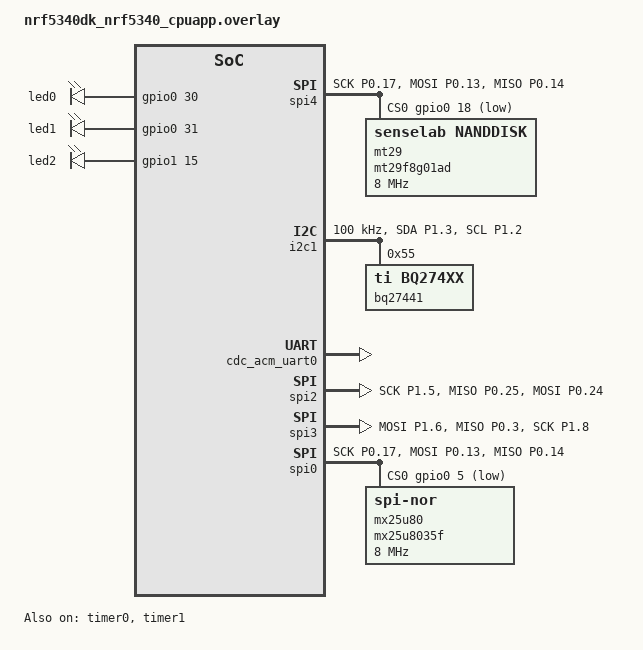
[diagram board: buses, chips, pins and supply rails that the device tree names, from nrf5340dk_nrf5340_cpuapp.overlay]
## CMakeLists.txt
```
# SPDX-License-Identifier: Apache-2.0

# This is a general purpose project created from MotionSenseHRV to be used for data collection.

# Ohio State SENSE LAB
cmake_minimum_required(VERSION 3.20.0)

list(APPEND ZEPHYR_EXTRA_MODULES ${CMAKE_CURRENT_SOURCE_DIR}/src/drivers)

find_package(Zephyr REQUIRED HINTS $ENV{ZEPHYR_BASE})
project(MotionSenseHrv)

set(CMAKE_OBJECT_PATH_MAX 380)
if((NOT CONFIG_DISK_DRIVER_FLASH) AND
   (NOT CONFIG_DISK_DRIVER_RAM) AND
   (NOT CONFIG_DISK_DRIVER_SDMMC))
	message(WARNING "No disk access settings detected." )
endif()
#
#we previously used GLOB_RECURSE, but that was deprecated since we want to have control over what code is included.
FILE(GLOB_RECURSE app_sources src/*.cc)
FILE(GLOB c_app_sources src/*.c)

target_compile_options(app PRIVATE -Wno-unused-function)
#eventually, remove the induvidual file in target_sources, and just refactor to move zephyr filesystem out.
#OR Keep Global Recuse on.
# also move the drivers over to a seperate folder.
target_sources(app PRIVATE ${app_sources} 
${c_app_sources} )

#if(CONFIG_BUILD_WITH_TFM)
#  target_include_directories(app PRIVATE
#    $<TARGET_PROPERTY:tfm,TFM_BINARY_DIR>/install/interface/include
#  )
#endif()
```

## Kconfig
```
# Copyright (c) 2019-2020 Nordic Semiconductor ASA
# SPDX-License-Identifier: Apache-2.0

config APP_WIPE_STORAGE
	bool "Option to clear the flash area before mounting"
	help
	  Use this to force an existing file system to be created.

choice
	prompt "Storage and file system type used by the application"
	default APP_MSC_STORAGE_NONE
	help
	  Specify the type of storage and file system.

config APP_MSC_STORAGE_NONE
	bool "Use RAM disk as block device"
	imply DISK_DRIVER_RAM

config APP_MSC_STORAGE_RAM
	bool "Use RAM disk and FAT file system"
	imply DISK_DRIVER_RAM
	imply FILE_SYSTEM
	imply FAT_FILESYSTEM_ELM

config APP_MSC_STORAGE_FLASH_FATFS
	bool "Use FLASH disk and FAT file system"
	imply DISK_DRIVER_FLASH
	imply FILE_SYSTEM
	imply FAT_FILESYSTEM_ELM

config APP_MSC_STORAGE_FLASH_LITTLEFS
	bool "Use FLASH disk and LittleFS"
	imply DISK_DRIVER_FLASH
	imply FILE_SYSTEM
	imply FILE_SYSTEM_LITTLEFS

config APP_MSC_STORAGE_SDCARD
	bool "Use SDHC and FAT file system"
	imply DISK_DRIVER_SDMMC
	imply FILE_SYSTEM
	imply FAT_FILESYSTEM_ELM

endchoice

config MASS_STORAGE_DISK_NAME
	default "MX25R64" if DISK_DRIVER_FLASH
	default "RAM" if DISK_DRIVER_RAM
	default "SD" if DISK_DRIVER_SDMMC

if DISK_DRIVER_FLASH

config FLASH_MAP
	default y

config FLASH_PAGE_LAYOUT
	default y

config FLASH_LOG_LEVEL
	default 3

if NORDIC_QSPI_NOR

config NORDIC_QSPI_NOR_FLASH_LAYOUT_PAGE_SIZE
	default 4096

endif # NORDIC_QSPI_NOR

endif # DISK_DRIVER_FLASH

config MSENSE3_BLUETOOTH_DATA_UPDATES
	bool "Use MotionSenseHRV3Updates"
	default n
	help 
		Enables the Previous MSense3 mode of data collection, which starts collection as soon as the device connects to usb
		and sends data all through bluetooth
		

menuconfig COLLECTION_REQUIRES_DATE_ID
	bool "Allows sensor collection only if the date time and id characteristics have been filled out by the central."
	default n

config USB_ALWAYS_ON
	bool "whether the usb mass storage driver is on during bluetooth collection"
	default n
	help
		Normally, when data collection starts the USB module turns off, preventing the user from being able to read the drive 
		while data collection is taking place. This KConfig disables this, allowing users to always see logs

config USB_WRITABLE
	bool "whether one can write or modify files via USB"
	default n
	help 
		If the device is plugged in via USB and this KConfig is not set, Users will not be able to create or write new files
		(they can still read them).
		for this to truly work, we must be using a file system driver that supports reading and writing, 
		like flash area (NOR) or dhara (NAND)

config MSENSE_USB_SECURITY
	bool "Configures USB security mode, which requires a password in order to enable to usb behavior. Not Currently Implemented."
	default n

config LOG_BACKEND_FS_BUFFER
    bool "file buffered log backend"
    depends on LOG
    select LOG_OUTPUT
    help
      When enabled, the double buffered filesystem backend (normally for ppg and accel) will be used for logging.

config LOG_LEVEL_IMU_COLLECTION
	int "level at which data from imu is printed in logs"
	default 3

config LOG_LEVEL_PPG_COLLECTION
	int "level at which data from ppg is printed in logs"
	default 3

config LOG_LEVEL_MAX30001
	int "level at which data from MAX30001 is printed in logs"
	default 3

source "Kconfig.zephyr"
```

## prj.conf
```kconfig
#CONFIG_NCS_SAMPLES_DEFAULTS=y

CONFIG_STDOUT_CONSOLE=y

# deprecated:
#CONFIG_CPLUSPLUS=y
#CONFIG_STD_CPP11=y
#CONFIG_NEWLIB_LIBC=y
#CONFIG_LIB_CPLUSPLUS=y

#CONFIG_DEBUG=n
CONFIG_DEBUG_OPTIMIZATIONS=n
#CONFIG_SIZE_OPTIMIZATIONS=y
#CONFIG_SPEED_OPTIMIZATIONS=y

# These KConfigs will dump the entire core into the logs. Useful for debugging a crash.
#CONFIG_DEBUG_COREDUMP=y
#CONFIG_DEBUG_COREDUMP_BACKEND_LOGGING=y
CONFIG_DEBUG_INFO=y
CONFIG_EXCEPTION_STACK_TRACE=y
CONFIG_RESET_ON_FATAL_ERROR=y

#Log config
CONFIG_LOG=y
CONFIG_LOG_DEFAULT_LEVEL=2
# LOG_MODE_MIMIMAL Processes logs in the thread that they are in.
CONFIG_LOG_MODE_MINIMAL=n
#CONFIG_LOG_MODE_DEFERRED=n
#CONFIG_LOG_MODE_IMMEDIATE=n
# this makes prink messages go through the LOG system.
CONFIG_LOG_PRINTK=y
# typically logging is seperate from printk, so this just let's printk output go to console.
CONFIG_PRINTK=y
CONFIG_LOG_MAX_LEVEL=4
# Additional Logging Settings
# this makes the logs have color according to their condition in the serial monitor or terminal.
# so, errors are red, and warnings are yellow.
# in the filesystem, you will need to have an ascii color text processor, otherwise you will see unknown characters and no colors.
CONFIG_LOG_BACKEND_SHOW_COLOR=y
# if we using the deffered log proessing, we have these options avalible:
# LOG_MODE_DEFFERED auto turns this on. deffered mode makes the logs go to a seperate thread instead, which we currently use.
CONFIG_LOG_PROCESS_THREAD=y
#CONFIG_LOG_PROCESS_THREAD_CUSTOM_PRIORITY=
# we need this since our usb takes a few seconds to initialize, and so we miss messages if we don't do a late log startup.
CONFIG_LOG_PROCESS_THREAD_STARTUP_DELAY_MS=8000
#CONFIG_LOG_PROCESS_TRIGGER_THRESHOLD=0
# THREAD_SLEEP_MS is how long the logging thread will periodically sleep after processing messages. 
CONFIG_LOG_PROCESS_THREAD_SLEEP_MS=4000
CONFIG_LOG_PROCESS_THREAD_STACK_SIZE=4096
CONFIG_LOG_BUFFER_SIZE=20000

# Custom Config we created to allow the usb to remain on even when data is collecting, so that we can see the logs. Without this we can't 
#see logs through USB.
CONFIG_USB_ALWAYS_ON=y

CONFIG_NRFX_RTC0=y

# The thread analyser is a cool logging tool that shows how full stacks are for running threads. It can be used to detect stack overflow errors.
CONFIG_THREAD_ANALYZER=y
CONFIG_THREAD_ANALYZER_USE_LOG=y
CONFIG_THREAD_ANALYZER_AUTO=y
CONFIG_THREAD_ANALYZER_AUTO_INTERVAL=10
CONFIG_THREAD_NAME=y
CONFIG_THREAD_MONITOR=y

# when working with the MSense Devices, the only debugging tool we have is the SEGGER_RTT and USB debug output. 
# We have a USB, but we have to set it up via CDC UART (CDC is a usb communication protocol) on device tree
# at the moment, it appears Segger RTT is required even for UART Console output.
CONFIG_USE_SEGGER_RTT=y
# LOG_BACKEND makes the logging avalible, while the CONSOLE option makes command output
CONFIG_LOG_BACKEND_RTT=y
CONFIG_RTT_CONSOLE=n
# Shell also allows commands to be sent
CONFIG_SHELL=n

#Outputs log through usb
CONFIG_LOG_BACKEND_UART=y
# same here, UART_CONSOLE allows commands to be sent while LOG_BACKEND_UART allows log messages to go out.
CONFIG_UART_CONSOLE=y

#CONFIG_RAM_CONSOLE=n

#CONFIG_LOG_BACKEND_FS=n
#CONFIG_LOG_BACKEND_FS_OUTPUT_CUSTOM=y

# Outputs log through USB
CONFIG_LOG_BACKEND_BLE=y
# Custom MSense File Uploading that uses the double buffer system (zephyrfilesystem.c) to output
CONFIG_LOG_BACKEND_FS_BUFFER=y

# Our MSense boards don't have a DCDC on them. This is necessary for the boards to function, or else they will brick!
#CONFIG_BOARD_ENABLE_DCDC_APP=n
#CONFIG_BOARD_ENABLE_DCDC_NET=n

# Clock Control. This KConfig Controls whether we use a Crystal (XTAL) or RC Oscilator.
CONFIG_CLOCK_CONTROL_NRF_K32SRC_RC=n
CONFIG_CLOCK_CONTROL_NRF_K32SRC_RC_CALIBRATION=n

CONFIG_CLOCK_CONTROL_NRF_K32SRC_XTAL=y

# LFXO bypass is for a rail-to-rail external clock source. This board uses
# the standard LFXO pin routing, so leave bypass disabled.
CONFIG_SOC_LFXO_BYPASS=n
CONFIG_SOC_LFXO_CAP_INT_9PF=y
CONFIG_SOC_HFXO_CAP_INTERNAL=y
CONFIG_SOC_HFXO_CAP_INT_VALUE_X2=25

#Gpio Config
CONFIG_GPIO=y

# On the 5340 dev kit, pins 0.02 and 0.03 are configured as pins for an NFC antenna. Since we are using those pins for ppg,
# we need to use this KConfig to make them behave like normal. Apparently setting it in device tree is not enough, we have to use this KConfig
CONFIG_NFCT_PINS_AS_GPIOS=y

# SPI Config
CONFIG_SPI=y
# we don't have any qspi periperals at the moment, everything is spi.
#CONFIG_NRFX_QSPI=y

#I2C config
CONFIG_I2C=y

# Generic Sensor Drivers that includes the battery monitor sensor.
CONFIG_SENSOR=y

# CMSIS config, which is a DSP and Math library
CONFIG_CMSIS_DSP=y
CONFIG_CMSIS_DSP_BASICMATH=y
CONFIG_CMSIS_DSP_COMPLEXMATH=n
CONFIG_CMSIS_DSP_CONTROLLER=n
CONFIG_CMSIS_DSP_DISTANCE=n
CONFIG_CMSIS_DSP_FASTMATH=y
CONFIG_CMSIS_DSP_FILTERING=y
CONFIG_CMSIS_DSP_MATRIX=y
CONFIG_CMSIS_DSP_STATISTICS=y
CONFIG_CMSIS_DSP_TRANSFORM=n
CONFIG_CMSIS_DSP_SUPPORT=y

# timer config
CONFIG_NRFX_TIMER0=y
CONFIG_NRFX_TIMER1=y

#FPU config
CONFIG_FPU=y
CONFIG_FP_HARDABI=y

# Library for buttons and LEDs
CONFIG_DK_LIBRARY=y

# Enable bluetooth and bonding
CONFIG_BT=y

#CONFIG_BT_BONDABLE=y
#CONFIG_BT_BONDING_REQUIRED=y

CONFIG_BT_DEVICE_APPEARANCE=833

CONFIG_BT_MAX_CONN=1

CONFIG_BT_PERIPHERAL=y
#CONFIG_BT_GAP_PERIPHERAL_PREF_PARAMS=y
# in BLE the host typically sets the minimum and maximum connection interval with which packets must be sent. 
# however, the client can still request preferred parameters and the host can decide if it wants to accept them.
CONFIG_BT_PERIPHERAL_PREF_MAX_INT=48
CONFIG_BT_PERIPHERAL_PREF_MIN_INT=24
CONFIG_BT_PERIPHERAL_PREF_LATENCY=3
# Units are 10 ms: 800 = 8 s, compliant with current Apple 6-18 s guidance (ADG section 55.6).
CONFIG_BT_PERIPHERAL_PREF_TIMEOUT=800
CONFIG_BT_DEVICE_NAME="MSense4PPG-"
CONFIG_BT_DEVICE_NAME_DYNAMIC=y
CONFIG_BT_DEVICE_NAME_MAX=16
CONFIG_BT_DEVICE_NAME_GATT_WRITABLE=n
CONFIG_HWINFO=y
CONFIG_CRC=y

#CONFIG_BT_CTLR=y
#CONFIG_BT_CTLR_TX_PWR_ANTENNA=-8
#CONFIG_BT_CTLR_TX_PWR_MINUS_40=y

# for now, we don't use security, but we can re-enable if we want it.
CONFIG_BT_SMP=n

# Enable device information service for bluetooth
CONFIG_BT_DIS=y
CONFIG_BT_DIS_MANUF="SenseLab"
CONFIG_BT_DIS_PNP=n
CONFIG_BT_DIS_MODEL="5.2.3 Utah Prod"
CONFIG_BT_DIS_SETTINGS=n
CONFIG_BT_MAX_PAIRED=1

# Enable Battery service settings
CONFIG_BT_BAS=y

 

# I belive we do this because the flash reset function has a lot of stack usage.
CONFIG_BT_RX_STACK_SIZE=8192

#DFU/FOTA settings
CONFIG_BOOTLOADER_MCUBOOT=y

CONFIG_NCS_SAMPLE_MCUMGR_BT_OTA_DFU=y
#CONFIG_MCUBOOT_GENERATE_CONFIRMED_IMAGE=y

#CONFIG_MCUMGR_LOG_LEVEL_DBG=n
#CONFIG_MCUMGR_SMP_BT_AUTHEN=n

# Where the bad block table is persisted. The NOR backend keeps it on the external
# NOR next to the file table, which needs no extra partition, so Partition Manager
# produces the same map as devices already in the field and they can still take a
# DFU update. Selecting RAW_NAND_BAD_BLOCK_STORAGE_SETTINGS instead moves it to the
# settings subsystem, which allocates a settings_storage partition and changes the
# map, breaking DFU for those devices.
CONFIG_RAW_NAND_BAD_BLOCK_STORAGE_NOR=y

# Only needed by the settings backend above. Enabling SETTINGS_NVS is what makes
# Partition Manager carve out settings_storage.
CONFIG_SETTINGS=n
#CONFIG_SETTINGS_NVS=y
#CONFIG_NVS=y

#CONFIG_SETTINGS_NVS_SECTOR_COUNT=8
# The default 0x2000 only gives NVS two sectors, one of which is always reserved
# for garbage collection. 0x4000 gives it four and matches FPROTECT_BLOCK_SIZE on
# the nRF5340, which the partition has to start on anyway, so nothing is wasted
# on alignment padding.
#CONFIG_BT_SETTINGS=y
#CONFIG_SETTINGS_RUNTIME=y

#CONFIG_SETTINGS_NONE=y

# not sure what this is
#CONFIG_MPU_ALLOW_FLASH_WRITE=y

CONFIG_TEST_RANDOM_GENERATOR=y
CONFIG_TIMER_RANDOM_GENERATOR=y

# Flash Driver Config
# CRC library, used to sanity check the file table stored on the NOR
CONFIG_CRC=y
CONFIG_SPI_NOR=y
CONFIG_FLASH=y
# QSPI Driver for QSPI Nor Flash. No longer used as we use NAND for storage.
CONFIG_NORDIC_QSPI_NOR=n
CONFIG_FLASH_MAP=y
CONFIG_FLASH_PAGE_LAYOUT=y
CONFIG_FLASH_LOG_LEVEL_INF=y
#CONFIG_SPI_NOR_FLASH_LAYOUT_PAGE_SIZE=4096

# Partition Manager Config

CONFIG_PM_EXTERNAL_FLASH_MCUBOOT_SECONDARY=n

# Disk Driver Config
CONFIG_DISK_DRIVER_FLASH=n
CONFIG_DISK_DRIVER_RAM=n
CONFIG_DISK_DRIVER_RAW_NAND=y
CONFIG_DISK_DRIVER_DHARA=n

CONFIG_RAW_NAND_BAD_BLOCK_SAVING=y
CONFIG_RAW_NAND_BAD_BLOCK_SIMULATION=y
# File System Config
CONFIG_FILE_SYSTEM=y
# needed because of our BT DFU external flash image which forces us to use partition manager.
CONFIG_PM_OVERRIDE_EXTERNAL_DRIVER_CHECK=y
CONFIG_MASS_STORAGE_DISK_NAME="SD"
#CONFIG_FILE_SYSTEM_LITTLEFS=y
# ELM Chan's fat filesystem library
CONFIG_FAT_FILESYSTEM_ELM=y
# we implement this dynamically by remounting the file system as read only.
CONFIG_FS_FATFS_READ_ONLY=n

# below config is necessary because this determines the buffer fatfs internally uses to store reads which we do at a size of 4096
CONFIG_FS_FATFS_MAX_SS=4096
CONFIG_FS_FATFS_EXFAT=n
CONFIG_FS_FATFS_MAX_ROOT_ENTRIES=4096
CONFIG_FS_FATFS_LFN=y

# we no longer use little fs since there is no built in computer file system support on USB mass.
#CONFIG_FS_LITTLEFS_CACHE_SIZE=128
#CONFIG_FS_LITTLEFS_READ_SIZE=16
#CONFIG_FS_LITTLEFS_PROG_SIZE=16

#USB related configs
CONFIG_USB_DEVICE_STACK=y
CONFIG_USB_DEVICE_PRODUCT="MSense4 USB Mass"
CONFIG_USB_DEVICE_PID=0x0008
CONFIG_USB_MASS_STORAGE=y

CONFIG_USB_MAX_POWER=100
CONFIG_USB_DEVICE_LOG_LEVEL_INF=y
# this log handles where the usb mass throws errors.
CONFIG_USB_MASS_STORAGE_LOG_LEVEL_ERR=y

CONFIG_USB_DEVICE_INITIALIZE_AT_BOOT=n
CONFIG_MASS_STORAGE_STACK_SIZE=4096

# Previous method of data gathering, where data from sensors is sent through bluetooth instead of the file system.
CONFIG_MSENSE3_BLUETOOTH_DATA_UPDATES=n

CONFIG_MSENSE_USB_SECURITY=n

# IMU and PPG logs
CONFIG_LOG_LEVEL_IMU_COLLECTION=3
CONFIG_LOG_LEVEL_PPG_COLLECTION=3

# General System Memory and stack Configs
CONFIG_SYSTEM_WORKQUEUE_STACK_SIZE=20192
CONFIG_SYSTEM_WORKQUEUE_PRIORITY=-5
#CONFIG_SYSTEM_WORKQUEUE_NO_YIELD=y

CONFIG_HEAP_MEM_POOL_SIZE=5384
CONFIG_MAIN_STACK_SIZE=20192

# File system encryption (src/fs_crypt.c): AES on the CryptoCell-312 through PSA.
# Bluetooth keeps using TinyCrypt; nothing here changes it.
CONFIG_NRF_SECURITY=y
CONFIG_MBEDTLS_PSA_CRYPTO_C=y
CONFIG_PSA_CRYPTO_DRIVER_CC3XX=y
CONFIG_PSA_CRYPTO_DRIVER_OBERON=n
CONFIG_PSA_WANT_KEY_TYPE_AES=y
CONFIG_PSA_WANT_AES_KEY_SIZE_128=y
CONFIG_PSA_WANT_ALG_ECB_NO_PADDING=y
# psa_crypto_init() also brings up the random number generator
CONFIG_PSA_WANT_GENERATE_RANDOM=y
CONFIG_MBEDTLS_ENABLE_HEAP=y
CONFIG_MBEDTLS_HEAP_SIZE=8192
```

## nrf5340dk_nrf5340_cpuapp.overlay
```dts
// press Ctrl+Space to bring up the completion menu and view the available nodes.

// You can also use the buttons in the sidebar to perform actions on nodes.
// Actions currently available include:

// * Enabling / disabling the node
// * Adding the bus to a bus
// * Removing the node
// * Connecting ADC channels

// For more help, browse the DeviceTree documentation at https://docs.zephyrproject.org/latest/guides/dts/index.html
// You can also visit the nRF DeviceTree extension documentation at https://nrfconnect.github.io/vscode-nrf-connect/devicetree/nrfdevicetree.html

/* Begin dk trim section, that removes all dev kit specific nodes. */

&spi1 {
    status = "disabled";
};

&spi4 {
	status = "disabled";
};

&qspi {
	status = "disabled";
};

&uart0 {
	status = "okay";
};

&i2c1 {
	status = "disabled";
};

&pwm0 {
	status = "disabled";
};

&led0 {
    status = "okay";
	gpios = <&gpio0 30 GPIO_ACTIVE_HIGH>;
};

&led1 {
    status = "okay";
    gpios = <&gpio0 31 GPIO_ACTIVE_HIGH>;
};

&led2 {
    status = "okay";
	gpios = <&gpio1 15 GPIO_ACTIVE_HIGH>;
};

&led3 {
    status = "disabled";
};

&button0 {
    status = "disabled";
};

&button1 {
    status = "disabled";
};

&button2 {
    status = "disabled";
};

&button3 {
    status = "disabled";
};

&gpio_fwd {
	status = "okay";
};

/* End dev kit trim section */

&timer0 {
    status = "okay";
};

&timer1 {
    status = "okay";
};

&arduino_adc {
    io-channel-map = <0 &adc 0>, <1 &adc 1>, <2 &adc 2>, <3 &adc 3>, <4 &adc 4>, <5 &adc 5>;
};

/ {
    aliases {
        customspi = &spi1;
		spi-flash0 = &mt29;
		spi-flash1 = &mx25u80;
    };
};

/ {
	chosen {
	
		//nordic,pm-ext-flash = &mt29;
		zephyr,console = &cdc_acm_uart0;
        zephyr,shell-uart = &cdc_acm_uart0;
		
		};
	};
	

///delete-node/ &storage_partition;

//uart cannot also be in operation with spi0, however, this means we have to use segger RTT, because uart is used for console output
&uart0 {
	status = "disabled";
};

 
&zephyr_udc0 {
    cdc_acm_uart0: cdc_acm_uart0 {
        compatible = "zephyr,cdc-acm-uart";
    };
};

&spi2 {
compatible = "nordic,nrf-spim";
	status = "okay";
	cs-gpios = <&gpio0 26 GPIO_ACTIVE_LOW>;
	pinctrl-0 = <&spi1_default>;
	pinctrl-1 = <&spi1_sleep>;
	pinctrl-names = "default", "sleep";

};

// We need to disable i2c1, since we are already using spi1 and it is no longer needed (can't have 2 devices on the same unit).
&i2c1 {
	compatible = "nordic,nrf-twim";
	status = "okay";

	clock-frequency = <I2C_BITRATE_STANDARD>;

	pinctrl-0 = <&battery_default>;
	pinctrl-1 = <&battery_sleep>;
	pinctrl-names = "default", "sleep";
	bq27441@55 {
		compatible = "ti,bq274xx";
        reg = <0x55>;
        design-voltage = <3700>;
        design-capacity = <300>;
        taper-current = <30>;
        terminate-voltage = <3000>;
	};
};

/* 
&i2c0 {
	status = "okay";
	compatible = "nordic,nrf-twim";
	pinctrl-0 = < &i2c1_default>;
	pinctrl-1 = <&i2c1_sleep>;
	pinctrl-names = "default", "sleep";
};
*/

&spi3{
	compatible = "nordic,nrf-spim";
	status = "okay";
	cs-gpios = <&gpio1 9 GPIO_ACTIVE_LOW>;
	pinctrl-0 = <&ppg_default>;
	pinctrl-1 = <&ppg_sleep>;
	pinctrl-names = "default", "sleep";
};

//External Flash, MX25 NOR 

&spi0 {
	status = "okay";
	pinctrl-0 = <&spi_flash_default>;
	pinctrl-1 = <&spi_flash_sleep>;
	pinctrl-names = "default", "sleep";
	cs-gpios = <&gpio0 5 GPIO_ACTIVE_LOW>;
	mx25u80: mx25u8035f@0 {
		compatible = "jedec,spi-nor";
		// size needs to be in bits for nor
		//size = <1073725440>;
		size = <8388608>;
		reg = <0>;
		spi-max-frequency = <8000000>;
		jedec-id = [c2 25 34];
		status = "okay";
	};

};

// External Flash, MT29 NAND

&spi4 {
	status = "okay";
	pinctrl-0 = < &spi_flash_default>;
	pinctrl-1 = <&spi_flash_sleep>;
	pinctrl-names = "default", "sleep";
	cs-gpios = <&gpio0 18 GPIO_ACTIVE_LOW>, <&gpio0 4 GPIO_ACTIVE_LOW>, <&gpio0 21 GPIO_ACTIVE_LOW>, <&gpio0 19 GPIO_ACTIVE_LOW>;
	mt29: mt29f8g01ad@0 {
		compatible = "senselab,nanddisk";
		// size parameter needs to be in bytes
		// 4294901760 bytes is aproximately 4 GB. Updated from 2147450880 bytes (1.99 GB)
		size = <4294901760>;
		reg = <0>;
		spi-max-frequency = <8000000>;
		jedec-id = [ff 2c 47];
		status = "okay";
	};

};

/* 
&qspi {
	status = "okay";
	pinctrl-0 = <&qspi_default>;
	pinctrl-1 = <&qspi_sleep>;
	pinctrl-names = "default", "sleep";
	mx66u: mx66u2g45g@0 {
		compatible = "nordic,qspi-nor";
		//compatible = "vnd,customflash";
		//compatible = "senselab,qspinor";
	reg = <0>;
	//MX25R64 supports only pp and pp4io
	writeoc = "pp4io";
	//MX25R64 supports all readoc options
	readoc = "read4io";
	sck-frequency = <8000000>;
	jedec-id = [c2 25 3c];
	sfdp-bfp = [
		e5 20 f1 ff  ff ff ff 03  44 eb 08 6b  08 3b 04 bb
		ee ff ff ff  ff ff 00 ff  ff ff 00 ff  0c 20 0f 52
		10 d8 00 ff  23 72 f5 00  82 ed 04 cc  44 83 68 44
		30 b0 30 b0  f7 c4 d5 5c  00 be 29 ff  f0 d0 ff ff
	];
	size = <67108864>;
	has-dpd;
	t-enter-dpd = <10000>;
	t-exit-dpd = <35000>;
	};
};
*/

&pinctrl {
	//spi 1, imu sensor
    spi1_default: spi1_default {
		group1 {
			psels = <NRF_PSEL(SPIM_SCK, 1, 5)>,
				<NRF_PSEL(SPIM_MISO, 0, 25)>,
				<NRF_PSEL(SPIM_MOSI, 0, 24)>;
		};
	};

	spi1_sleep: spi1_sleep {
		group1 {
			psels = <NRF_PSEL(SPIM_SCK, 1, 5)>,
				<NRF_PSEL(SPIM_MISO, 0, 25)>,
				<NRF_PSEL(SPIM_MOSI, 0, 24)>;
			low-power-enable;
		};
	};

	
	//spi 4, ppg sensor
	ppg_default: ppg_default {
		group1 {
			psels = <NRF_PSEL(SPIM_MOSI, 1, 6)>, <NRF_PSEL(SPIM_MISO, 0, 3)>, <NRF_PSEL(SPIM_SCK, 1, 8)>;
		};
	};

	ppg_sleep: ppg_sleep {
		group1{
			psels = <NRF_PSEL(SPIM_MOSI, 1, 6)>, <NRF_PSEL(SPIM_MISO, 0, 3)>, <NRF_PSEL(SPIM_SCK, 1, 8)>;
			low-power-enable;
		};
	};
	
	 
	//battery, on i2c0
	battery_default: battery_default {
		group1 {
			psels = <NRF_PSEL(TWIM_SDA, 1, 3)>,
				<NRF_PSEL(TWIM_SCL, 1, 2)>;
		};
	};

	battery_sleep: battery_sleep {
		group1 {
			psels = <NRF_PSEL(TWIM_SDA, 1, 3)>,
				<NRF_PSEL(TWIM_SCL, 1, 2)>;
			low-power-enable;
		};
	};

	
	spi_flash_default: spi_flash_default {
		group1 {
			psels = <NRF_PSEL(SPIM_SCK, 0, 17)>,
				<NRF_PSEL(SPIM_MOSI, 0, 13)>,
				<NRF_PSEL(SPIM_MISO, 0, 14)>;
				
		};
	};
	
	spi_flash_sleep: spi_flash_sleep {
		group1 {
			psels = <NRF_PSEL(SPIM_SCK, 0, 17)>,
			<NRF_PSEL(SPIM_MOSI, 0, 13)>,
			<NRF_PSEL(SPIM_MISO, 0, 14)>;
			low-power-enable;
		};
	};

};
```

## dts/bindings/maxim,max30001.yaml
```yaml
description: MAX30001 ECG analog front-end on SPI

compatible: "maxim,max30001"

include: ["spi-device.yaml"]

properties:
  reg:
    required: true

  intb-gpios:
    type: phandle-array
    description: MAX30001 INTB interrupt GPIO.

  intb2-gpios:
    type: phandle-array
    description: MAX30001 INTB2 interrupt GPIO.
```

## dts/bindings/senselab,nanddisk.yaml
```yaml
description: |
  Zephyr MMC disk node. A binding with this compatible present within an SD
  host controller device node indicates that an SDMMC disk is attached to that
  SD bus. This binding will enable that disk to be used with the disk driver
  API and any subsystems that utilize it.

compatible: "senselab,nanddisk"

include: ["spi-device.yaml", "jedec,spi-nor-common.yaml"]

properties:
  reg:
    required: true

  jedec-id:
    required: true

  size:
    type: int
    description: |
      The size of the flash in bytes.  
```

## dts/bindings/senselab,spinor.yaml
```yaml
description: |
  Zephyr MMC disk node. A binding with this compatible present within an SD
  host controller device node indicates that an SDMMC disk is attached to that
  SD bus. This binding will enable that disk to be used with the disk driver
  API and any subsystems that utilize it.

compatible: "senselab,spinor"

include: ["spi-device.yaml", "jedec,spi-nor-common.yaml"]

properties:
  reg:
    required: true

  jedec-id:
    required: true

  size:
    type: int
    description: |
      The size of the flash in bytes.  
```

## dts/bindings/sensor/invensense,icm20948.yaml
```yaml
# SPDX-License-Identifier: Apache-2.0

description: |
  ICM-20948 accelerometer-only SPI interface used by the MotionSense ECG PCB.

compatible: "invensense,icm20948"

include: spi-device.yaml

properties:
  int-gpios:
    type: phandle-array
    required: true
    description: |
      INT1 data-ready signal. The ICM-20948 is configured as active-high,
      push-pull, and pulse mode.

  fsync-gpios:
    type: phandle-array
    required: true
    description: |
      FSYNC input driven inactive by the host while frame synchronization is
      unused.
```

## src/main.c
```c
/*
 * Copyright (c) 2016 Intel Corporation
 *
 * SPDX-License-Identifier: Apache-2.0
 */

#include <zephyr/kernel.h>
#include <zephyr/devicetree.h>
#include <zephyr/drivers/gpio.h>
#include <zephyr/drivers/spi.h>
#include <zephyr/drivers/i2c.h>
#include <zephyr/drivers/sensor.h>
#include "drivers/nand/nand_disk.h"
#include <nrfx.h>
#include <nrfx_timer.h>
#include <nrfx_uarte.h>
#include <zephyr/logging/log.h>
#include <zephyr/usb/usb_device.h>
#include "batterymonitordt.h"
#include "ppgSensor.h"
#include "imuSensor.h"
#include "common.h"
#include "BLEService.h"
#include "device_identity.h"
#include "fs_crypt_key.h"
#include "zephyrfilesystem.h"
#include <zephyr/shell/shell.h>
#include <zephyr/bluetooth/bluetooth.h>
#include <zephyr/bluetooth/hci.h>
#include <zephyr/bluetooth/uuid.h>
#include <string.h>

LOG_MODULE_REGISTER(main, 3);

/* 1000 msec = 1 sec */
#define SLEEP_TIME_MS 6000

/* The devicetree node identifier for the "led0" alias. */
#define LED_NODE DT_ALIAS(led0)
#define LED1_NODE DT_ALIAS(led1)
#define PPG_POWER_NODE DT_ALIAS(led2) 

// define our red and green leds
#define LED_PIN DT_GPIO_PIN(LED_NODE, gpios)
#define LED1_PIN DT_GPIO_PIN(LED1_NODE, gpios)

#define LED_FLAGS DT_GPIO_FLAGS(LED0_NODE, gpios)

#define PPG_POWER_PIN DT_GPIO_PIN(PPG_POWER_NODE, gpios)
#define PPG_POWER_FLAGS DT_GPIO_FLAGS(PPG_POWER_NODE, gpios)

const struct device* gpio0_device;
const struct device* gpio1_device;

/* SPI Definitions */

/*
------------------------------------------------------------------------------------
SPI Mode    CPOL 	CPHA 	Clock Polarity  Clock Phase Used to
                                in Idle State 	Sample and/or Shift the Data
------------------------------------------------------------------------------------
0               0         0 	Logic low 	Data sampled on rising edge and
                                                shifted out on the falling edge
1               0         1 	Logic low 	Data sampled on the falling edge and
                                                shifted out on the rising edge
2               1         1 	Logic high 	Data sampled on the falling edge and
                                                shifted out on the rising edge
3               1         0 	Logic high 	Data sampled on the rising edge and
                                                shifted out on the falling edge
-------------------------------------------------------------------------------------
*/
// SPI Mode-3 IMU
struct spi_config spi_cfg_imu =
{
    .frequency = 4000000,
    .operation = SPI_WORD_SET(8) | SPI_TRANSFER_MSB |
                 SPI_MODE_CPOL | SPI_MODE_CPHA,
    .slave = 0,
    // this should work, but for some reason it doesn't. However, this might work without
    // the cs field anyway, apparently it is auto managed, so test first
    //.cs = SPI_CS_CONTROL_PTR_DT(DT_NODELABEL(spi2), 0)
    };

// SPI Mode-3 PPG
struct spi_config spi_cfg_ppg = {
    .frequency = 4000000,
    .operation = SPI_WORD_SET(8) | SPI_TRANSFER_MSB |
                 SPI_MODE_CPOL | SPI_MODE_CPHA,
    .slave = 0,
    /* only in version 2.5: .cs= {
  .delay = 0,
  .gpio = {.pin = 15, .dt_flags=GPIO_ACTIVE_LOW, }
  },
  */
};

// Now we define the cs pins

struct spi_cs_control imu_cs = {
    .delay = 0,
    .gpio = {.pin = 26, .dt_flags = GPIO_ACTIVE_LOW}};

struct spi_cs_control ppg_cs = {
    .delay = 0,
    .gpio = {
        .pin = 9,
        .dt_flags = GPIO_ACTIVE_LOW,
    }};

const struct device *spi_dev_ppg, *spi_dev_imu;
const struct device *i2c_dev;

#define DIS_FW_REV_STR CONFIG_BT_DIS_FW_REV_STR
#define DIS_FW_REV_STR_LEN (sizeof(DIS_FW_REV_STR))

#define DIS_HW_REV_STR CONFIG_BT_DIS_HW_REV_STR
#define DIS_HW_REV_STR_LEN (sizeof(DIS_HW_REV_STR))

#define DIS_MANUF CONFIG_BT_DIS_MANUF
#define DIS_MANUF_LEN (sizeof(DIS_MANUF))

#define DIS_MODEL CONFIG_BT_DIS_MODEL
#define DIS_MODEL_LEN (sizeof(DIS_MODEL))

static K_SEM_DEFINE(ble_init_ok, 0, 1);

uint32_t global_counter;

#define AD_FIELD_OVERHEAD 2U
#define AD_FLAGS_ENCODED_LEN (AD_FIELD_OVERHEAD + 1U)
#define AD_SERVICE_DATA_LEN (BT_UUID_SIZE_128 + MSENSE_DEVICE_ID_LEN)
#define AD_SERVICE_DATA_ENCODED_LEN (AD_FIELD_OVERHEAD + AD_SERVICE_DATA_LEN)
#define SCAN_RESPONSE_NAME_ENCODED_LEN (AD_FIELD_OVERHEAD + MSENSE_BLE_NAME_LEN)

static uint8_t advertising_service_data[AD_SERVICE_DATA_LEN] = {
    CONTROL_SERVICE_UUID,
};

static struct bt_data ad[] = {
    BT_DATA_BYTES(BT_DATA_FLAGS, (BT_LE_AD_GENERAL | BT_LE_AD_NO_BREDR)),
    BT_DATA(BT_DATA_SVC_DATA128, advertising_service_data,
            sizeof(advertising_service_data)),
};

static struct bt_data sd[] = {
    {
        .type = BT_DATA_NAME_COMPLETE,
        .data = NULL,
        .data_len = 0U,
    },
};

BUILD_ASSERT(MSENSE_DEVICE_ID_LEN == 8U, "Device ID must be 64 bits");
BUILD_ASSERT(MSENSE_BLE_NAME_LEN == 16U, "BLE name length changed unexpectedly");
BUILD_ASSERT(sizeof(advertising_service_data) == 24U,
             "Service data must contain UUID and device ID");
BUILD_ASSERT(AD_FLAGS_ENCODED_LEN + AD_SERVICE_DATA_ENCODED_LEN <=
             BT_GAP_ADV_MAX_ADV_DATA_LEN,
             "Primary advertising data exceeds the legacy limit");
BUILD_ASSERT(SCAN_RESPONSE_NAME_ENCODED_LEN <= BT_GAP_ADV_MAX_ADV_DATA_LEN,
             "Scan response name exceeds the legacy limit");

// Shell Commands for entering in the terminal, in case a bluetooth command is not avalible.
SHELL_CMD_REGISTER(reset, NULL, "Resets Device", NVIC_SystemReset);
SHELL_CMD_REGISTER(full_reset, NULL, "Resets Storage and Device", reset_device);

// Setting up the device information service
static int settings_runtime_load(void)
{

/*
  settings_runtime_set("bt/dis/model",
                       DIS_MODEL, DIS_MODEL_LEN);
  settings_runtime_set("bt/dis/manuf",
                       DIS_MANUF, DIS_MANUF_LEN);
*/
  return 0;
}

void usb_status_cb(enum usb_dc_status_code status, const uint8_t *param){
    
  LOG_INF("USB Status: %d", status);

  // CONNECTED/DISCONNECTED are raised on VBUS detect/remove, so update the charging bit right away
  // instead of waiting for the next battery_maintenance() pass.
  if (status == USB_DC_CONNECTED || status == USB_DC_DISCONNECTED){
    update_charging_state();
  }

}

static void write_uuid_file(void)
{
  bt_addr_le_t address = {0};
  size_t count = 1;
  char addr_str[BT_ADDR_LE_STR_LEN];
  int result;

  bt_id_get(&address, &count);
  bt_addr_le_to_str(&address, addr_str, sizeof(addr_str));

  result = write_ble_uuid(addr_str, bt_get_name(),
                          msense_device_identity_hex());
  if (result < 0) {
    LOG_ERR("Unable to write uuid.txt: %d", result);
  }
}

static void le_param_updated(struct bt_conn *conn, uint16_t interval, uint16_t latency, uint16_t timeout)
{
  struct bt_conn_info info;
  char addr[BT_ADDR_LE_STR_LEN];

  if (bt_conn_get_info(conn, &info))
    printk("Could not parse connection info\n");
  else
  {
    bt_addr_le_to_str(bt_conn_get_dst(conn), addr, sizeof(addr));
    printk("Connection parameters updated!	\n\
      Connected to: %s						\n\
      New Connection Interval: %u				\n\
      New Slave Latency: %u					\n\
      New Connection Supervisory Timeout: %u	\n",
           addr, info.le.interval, info.le.latency, info.le.timeout);
  }
}

static struct bt_conn_cb conn_callbacks = {
    .connected = connected,
    .disconnected = disconnected,
    //.le_param_req = le_param_req,
    .le_param_updated = le_param_updated};

static void bt_ready(int err)
{
  if (err)
  {
    printk("BLE init failed with error code %d\n", err);
    return;
  }
  else
    printk("BLE init success\n");

  #if CONFIG_BT_SETTINGS
    settings_load();
  #endif

  // Configure connection callbacks
  bt_conn_cb_register(&conn_callbacks);

  err = bt_set_name(msense_device_identity_name());
  if (err) {
    LOG_ERR("Unable to set generated BLE name: %d", err);
    return;
  }

  memcpy(&advertising_service_data[BT_UUID_SIZE_128],
         msense_device_identity_bytes(), MSENSE_DEVICE_ID_LEN);
  sd[0].data = msense_device_identity_name();
  sd[0].data_len = MSENSE_BLE_NAME_LEN;

  // Start advertising
  const struct bt_le_adv_param v = {
      .id = BT_ID_DEFAULT,
      .sid = 0,
      .secondary_max_skip = 0,
      .options = BT_LE_ADV_OPT_CONNECTABLE | BT_LE_ADV_OPT_USE_IDENTITY,
      .interval_min = BT_GAP_ADV_FAST_INT_MIN_2,
      .interval_max = BT_GAP_ADV_FAST_INT_MAX_2,
      .peer = NULL};

  // if this doesn't work we can use
  /* 
  static struct bt_le_adv_param *adv_param = BT_LE_ADV_PARAM((BT_LE_ADV_OPT_CONNECTABLE|BT_LE_ADV_OPT_USE_IDENTITY), 
                800, //Min Advertising Interval 500ms (800*0.625ms) 
                801, //Max Advertising Interval 500.625ms (801*0.625ms)
                NULL); // Set to NULL for undirected advertising
  */
  err = bt_le_adv_start(&v, ad, ARRAY_SIZE(ad), sd, ARRAY_SIZE(sd));
  if (err)
    printk("Advertising failed to start (err %d)\n", err);
  else
  {
    printk("Advertising started\n");
  }

  k_sem_give(&ble_init_ok);

  write_uuid_file();
  #ifndef CONFIG_DEBUG
  
    if (!security_lock){
      usb_enable(usb_status_cb);
    }
    //k_sleep(K_SECONDS(10));
    #if CONFIG_DISK_DRIVER_RAW_NAND
    set_read_only(true);
  #endif
  #endif
}

// Initialize BLE
static void ble_init(void)
{
  int err;

  
  err = bt_enable(bt_ready);
  if (err)
  {
    printk("BLE initialization failed\n");
  }

  //err = bt_id_create(BT_ADDR_LE_ANY, NULL);
  if (!err)
    printk("Bluetooth initialized\n");
  else
  {
    printk("BLE initialization did not complete in time\n");
  }
  if (err)
    printk("Bluetooth init failed (err %d)\n", err);
}

// Timer handler that periodically executes commands with a period,
// which is defined by the macro-variable TIMER_MS
static void spi_init(void)
{
  
  // device_get_binding is used for runtime aquisition of a device object. We can still use it but we have to be carefull to select the right names
  const char *const spiName_imu = "spi@9000";
  const char *const spiName_ppg = "spi@c000";

  spi_dev_imu = DEVICE_DT_GET(DT_NODELABEL(spi2)); 
  spi_dev_ppg = DEVICE_DT_GET(DT_NODELABEL(spi3));
  // device_get_binding(spiName_imu);
  //spi_dev_ppg = device_get_binding(spiName_ppg);

  if (!device_is_ready(gpio0_device))
  {
    printk("Could not get GPIO_0\n");
    return;
  }

  if (!device_is_ready(gpio1_device))
  {
    printk("Could not get GPIO_1\n");
    return;
  }
  if (spi_dev_imu == NULL || !device_is_ready(spi_dev_imu))
  {
    printk("Could not get %s \n", spiName_imu);
    return;
  }

  if (spi_dev_ppg == NULL || !device_is_ready(spi_dev_ppg))
  {
    printk("Could not get %s \n", spiName_ppg);
    return;
  }
  
  imu_cs.gpio.port = gpio0_device;
  ppg_cs.gpio.port = gpio1_device;
  
  
  spi_cfg_imu.cs = imu_cs;
  spi_cfg_ppg.cs = ppg_cs; // version 2.5: .gpio.port = gpio1_device;
  
}

void spi_verify_sensor_ids()
{
  
  if (device_is_ready(spi_dev_imu))
  {
    getIMUID();
  }
  else
  {
    LOG_WRN("IMU not ready, setup avoided");
  }
  
  k_sleep(K_SECONDS(1));

  if (device_is_ready(spi_dev_ppg))
  {
    read_ppg_chip_id();
  }
  else
  {
    LOG_WRN("ppg not ready, setup was avoided");
  }
}

static void i2c_init(void)
{

  printk("The I2C Init started\n");
  i2c_dev = DEVICE_DT_GET(DT_NODELABEL(i2c1));
  if (!device_is_ready(i2c_dev))
  {
    printk("Binding failed to i2c.");
    return;
  }
  // Previously we used to set values, but these are now set by device tree.
}

#define WORKQUEUE_PRIORITY 8
#define WORKQUEUE_STACK_SIZE 20048
K_THREAD_STACK_DEFINE(my_stack_area, WORKQUEUE_STACK_SIZE);

void battery_maintenance()
{
  const struct device *const dev = DEVICE_DT_GET_ONE(ti_bq274xx);
  dt_update_battery(dev, true);
  
  //battery_lvl = bt_bas_get_battery_level();
  #ifndef CONFIG_MSENSE3_BLUETOOTH_DATA_UPDATES
  if (battery_level < 5){
    // if this is our first time
    if (!battery_low){
      battery_low = true;
      LOG_WRN("battery low, turning off file logs and data collection.");
      LOG_INF("logs and data collection will resume once battery is sufficiently charged (>15 percent)");
    }   
  }
  else if (battery_level > 15){
    if (battery_low){
    LOG_INF("resuming log after battery improved");
    }
    battery_low = false;
  } 

  if (collecting_data || host_wants_collection){
        if (battery_low && collecting_data){
            
            start_stop_device_collection(false);
        }
        else if (!battery_low && host_wants_collection && !collecting_data){

            start_stop_device_collection(true);
            
        }
  }
  #endif
    
}

void blink_led(gpio_pin_t pin){
  gpio_pin_set(gpio0_device, pin, 1);
  k_sleep(K_MSEC(200));
  gpio_pin_set(gpio0_device, pin, 0);
}

void storage_clear_led(){
  gpio_pin_set(gpio0_device, LED1_PIN, 1);
}

int main(void)
{
	int identity_err;

  printk("Starting Application... \n");
  LOG_INF("Starting Logging...\n");

	identity_err = msense_device_identity_init();
	if (identity_err) {
		LOG_ERR("Unable to initialize factory device identity: %d", identity_err);
	}

	// Load the file system encryption key and self-test the crypto hardware.
	// The disk driver does not encrypt yet, so a failure here is only logged.
	int crypt_err = fs_crypt_init(fs_crypt_dev_data_key, fs_crypt_dev_tweak_key);
	if (crypt_err) {
		LOG_ERR("fs_crypt init failed: %d", crypt_err);
	} else {
		LOG_INF("fs_crypt ready, hardware AES self-test passed");
	}
  
  
  
  k_sleep(K_SECONDS(1));
  // Setup our Flash Filesystem
  setup_disk();
  k_sleep(K_SECONDS(1));
  #ifdef CONFIG_DEBUG  
  #if CONFIG_DISK_DRIVER_RAW_NAND
    set_read_only(true);
  #endif
  #endif

  #ifdef CONFIG_MSENSE_USB_SECURITY
    security_lock = true;
  #endif

  
  

  gpio0_device = DEVICE_DT_GET(DT_NODELABEL(gpio0));
  gpio1_device = DEVICE_DT_GET(DT_NODELABEL(gpio1));
  
  int ret;
  // Initialize our 2 LED pins and 5V PPG Power Pin
  ret = gpio_pin_configure(gpio0_device, LED_PIN, GPIO_OUTPUT_INACTIVE | LED_FLAGS);
  ret = gpio_pin_configure(gpio0_device, LED1_PIN, GPIO_OUTPUT_INACTIVE | LED_FLAGS);
  ret = gpio_pin_configure(gpio1_device, PPG_POWER_PIN, GPIO_OUTPUT_ACTIVE | PPG_POWER_FLAGS);
  // initialize imu ground pin
  ret = gpio_pin_configure(gpio0_device, 27, GPIO_OUTPUT_INACTIVE);
  if (ret < 0)
  {
    printk("Error: Can't initialize LED");
    // return;
  }
  
  // Init, verify ID and config sensors
  
  spi_init();
  spi_verify_sensor_ids();

  i2c_init();

  // Shutdown our ppg and imu sensors until we need to get data from them
  ppg_sleep();
  motion_sleep();

  /*struct k_work_queue_config cfg = {
    .name = "my_custom_workq",
    .no_yield = false
  };*/

  // Start Threads for all our sensor tasks
  // This is the file system workqueue (workqueues are threads that process items in a queue), it processes uploading files to the filesystem. 
  k_work_queue_init(&my_work_q);
  k_work_queue_start(&my_work_q, my_stack_area,
                     K_THREAD_STACK_SIZEOF(my_stack_area), WORKQUEUE_PRIORITY, NULL);
  // Handles reading from the motion sensor and ppg sensor. This is the system workqueue, which zephyr creates by default
  // and is a different queue from the user created file system workqueue 
  k_work_init(&my_motionSensor.work, motion_data_timeout_handler);
  k_work_init(&my_ppgSensor.work, read_ppg_fifo_buffer);
  // sends enmo and accelerometer
  k_work_init(&my_motionData.work, motion_notify);
#ifdef CONFIG_MSENSE3_BLUETOOTH_DATA_UPDATES
  // These items all handle sending data across bluetooth

  k_work_init(&my_ppgDataSensor.work, ppgData_notify);
#endif

  // these are our file system workqueue objects
  k_work_init(&ppg_work_item.work, work_write);
  ppg_work_item.sensor = ppg;

  k_work_init(&accel_work_item.work, work_write);
  accel_work_item.sensor = accelorometer;
  
  k_work_init(&log_work_item.work, work_write);
  log_work_item.sensor = customlog;
  k_thread_name_set(&my_work_q.thread, "file_sys");
  const char *name = k_thread_name_get(&my_work_q.thread);
  LOG_INF("file workqueue thead: %s", name);
  if (identity_err == 0) {
    ble_init();
  } else {
    LOG_ERR("BLE advertising disabled because device identity is unavailable");
  }
  
  get_storage_percent_full();
  
  
  // we set global update at 9 so that when we are entering the while loop, we will check the storage & battery.
  int global_update = 9;
  int update_time = SLEEP_TIME_MS;
  
  
  while (1)
  {
    
    //printk("%d %d\n", connectedFlag, collecting_data);

    global_update++;
    if (global_update >= 100){
      global_update = 0;
    }

    if (global_update % 5 == 0){
      uint64_t current_time_value = get_current_unix_time();
      LOG_INF("status update, time %llu", current_time_value);
      LOG_INF("connected: %d, collecting: %d", connectedFlag, collecting_data);
      battery_maintenance();
      print_flash_status_info();
      
    }

    if (!connectedFlag){
    // blink the LED while we aren't connected.
      blink_led(LED_PIN);
    }
    else {
      // When Connected, LED instead only blinks once every 10 cycles
      if (global_update % 10 == 0){
        blink_led(LED_PIN);
      }
    }
      
    
    if (collecting_data){
        blink_led(LED1_PIN);
    }

    k_msleep(update_time);
    
  }
  return 0;
}
```

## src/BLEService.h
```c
#ifndef BLESERVICE_H_
#define BLESERVICE_H_
#include <zephyr/types.h>
#include <sys/types.h>
#include "common.h"
#include <zephyr/bluetooth/bluetooth.h>

extern bool connectedFlag;
extern bool collecting_data;
extern bool host_wants_collection;
extern bool battery_low;
extern bool file_system_full;
extern bool file_system_malfunction;
extern bool battery_charging;

#define PPG_DATA_LEN 18
#define PPG_DATA_UNFILTER_LEN 12
#define CONFIG_RX_DATA_LEN 6
#define PPGQUALITY_DATA_LEN 4

// BLE CONFIG COMMAND
#define BLE_CONFIG_SENSOR_ENABLE 0x00
#define BLE_CONFIG_LED_INTENSITY_GREEN 0x03
#define BLE_CONFIG_LED_INTENSITY_IR 0x04
#define BLE_CONFIG_SAMPLING_RATE_PPG 0x06

// BLE CONFIG DATA
#define PPG_ENABLE 0x01
#define PPG_BLE_ENABLE 0x01

#define PPG_200_FS 0x01
#define PPG_100_FS 0x02
#define PPG_50_FS 0x03
#define PPG_25_FS 0x04

#define PPG_FIXED_256HZ_STATUS (PPG_50_FS << 4)

// Main Service UUID 
#define CONTROL_SERVICE_UUID  0x1F, 0x35, 0xBD, 0x4B, 0xAE, 0xD0, 0x68, 0x9C, \
  0xE2, 0x48, 0x81, 0x1D, 0x30, 0xC9, 0x39, 0xDA    

#define UPDATE3_SERVICE_UUID  0x1F, 0x35, 0xBD, 0x4B, 0xAE, 0xD0, 0x68, 0x9C, \
  0xE2, 0x48, 0x81, 0x1D, 0x20, 0xC9, 0x39, 0xDA 

// Configuration characteristic UUID
#define RX_CHARACTERISTIC_UUID  0x1F, 0x35, 0xBD, 0x4B, 0xAE, 0xD0, 0x68, 0x9C, \
  0xE2, 0x48, 0x81, 0x1D, 0x21, 0xC9, 0x39, 0xDA       
    
	
// PPG data characteristic UUID
#define PPG_TX_CHARACTERISTIC_UUID  0x1F, 0x35, 0xBD, 0x4B, 0xAE, 0xD0, 0x68, 0x9C, \
  0xE2, 0x48, 0x81, 0x1D, 0x23, 0xC9, 0x39, 0xDA         
                                           
   
// PPG Singal quality descriptor characteristic UUID
#define PPG_QUALITY_CHARACTERISTIC_UUID  0x1F, 0x35, 0xBD, 0x4B, 0xAE, 0xD0, 0x68, 0x9C, \
  0xE2, 0x48, 0x81, 0x1D, 0x27, 0xC9, 0x39, 0xDA   

#define WRITE_ENABLE_CHARACTERISTIC_UUID 0x1F, 0x35, 0xBD, 0x4B, 0xAE, 0xD0, 0x68, 0x9C, \
  0xE2, 0x48, 0x81, 0x1D, 0x31, 0xC9, 0x39, 0xDA

#define WRITE_DATE_CHARACTERISTIC_UUID 0x1F, 0x35, 0xBD, 0x4B, 0xAE, 0xD0, 0x68, 0x9C, \
  0xE2, 0x48, 0x81, 0x1D, 0x32, 0xC9, 0x39, 0xDA

#define WRITE_PATIENT_CHARACTERISTIC_UUID 0x1F, 0x35, 0xBD, 0x4B, 0xAE, 0xD0, 0x68, 0x9C, \
  0xE2, 0x48, 0x81, 0x1D, 0x33, 0xC9, 0x39, 0xDA

#define WRITE_RESET_CHARACTERISTIC_UUID 0x1F, 0x35, 0xBD, 0x4B, 0xAE, 0xD0, 0x68, 0x9C, \
  0xE2, 0x48, 0x81, 0x1D, 0x34, 0xC9, 0x39, 0xDA

#define WRITE_DEVICE_NAME_CHARACTERISTIC_UUID 0x1F, 0x35, 0xBD, 0x4B, 0xAE, 0xD0, 0x68, 0x9C, \
  0xE2, 0x48, 0x81, 0x1D, 0x35, 0xC9, 0x39, 0xDA

#define STATUS_SERVICE_UUID 0x1F, 0x35, 0xBD, 0x4B, 0xAE, 0xD0, 0x68, 0x9C, \
  0xE2, 0x48, 0x81, 0x1D, 0x40, 0xC9, 0x39, 0xDA

#define READ_STORAGE_LEFT_UUID 0x1F, 0x35, 0xBD, 0x4B, 0xAE, 0xD0, 0x68, 0x9C, \
  0xE2, 0x48, 0x81, 0x1D, 0x41, 0xC9, 0x39, 0xDA

#define READ_STATUS_REGISTER_UUID 0x1F, 0x35, 0xBD, 0x4B, 0xAE, 0xD0, 0x68, 0x9C, \
  0xE2, 0x48, 0x81, 0x1D, 0x42, 0xC9, 0x39, 0xDA

#define READ_UPTIME_UUID 0x1F, 0x35, 0xBD, 0x4B, 0xAE, 0xD0, 0x68, 0x9C, \
  0xE2, 0x48, 0x81, 0x1D, 0x43, 0xC9, 0x39, 0xDA

/* Legacy motion-update UUIDs retained for client compatibility. */
#define TIMING_UPDATE_SERVICE_UUID 0x1F, 0x35, 0xBD, 0x4B, 0xAE, 0xD0, 0x68, 0x9C, \
  0xE2, 0x48, 0x81, 0x1D, 0x50, 0xC9, 0x39, 0xDA

#define TIMING_UPDATE_CHARACTERISTIC_UUID 0x1F, 0x35, 0xBD, 0x4B, 0xAE, 0xD0, 0x68, 0x9C, \
  0xE2, 0x48, 0x81, 0x1D, 0x51, 0xC9, 0x39, 0xDA

/** @brief Callback type for when new data is received. */
typedef void (*data_rx_cb_t)(uint8_t *data, uint8_t length);

struct bleDataPacket {
    struct k_work work;
    uint8_t *dataPacket;
    uint8_t packetLength;
}; 

void connected(struct bt_conn *conn, uint8_t err);
void disconnected(struct bt_conn *conn, uint8_t reason);

int general_ble_notification(uint8_t* data, uint8_t len, int service, int characteristic);
void status_reg_ble_notification();

int storage_ble_notification(uint8_t* data, uint8_t len);

void ppgData_notify(struct k_work *item);

/**
 * @brief Start the collection-local RTC0 counter at 512 Hz.
 *
 * The counter is cleared before it starts. This API is called only by the
 * collection-mode lifecycle while its mutex is held.
 */
int rtc0_collection_counter_start(void);

/**
 * @brief Stop and uninitialize the collection-local RTC0 counter.
 */
void rtc0_collection_counter_stop(void);

/**
 * @brief Read the active 32-bit wrap-extended RTC0 counter in 512 Hz ticks.
 *
 * The 24-bit hardware counter is extended in software and wraps naturally
 * after 2^32 ticks. Callers must provide a non-NULL output pointer and must
 * tolerate -EACCES outside collection mode.
 */
int rtc0_collection_counter_get(uint32_t *ticks);

/**
 * @brief Start 3-second BLE timing notifications from the RTC0 compare event.
 *
 * This must be called after the 512 Hz collection counter is running.
 */
int rtc0_collection_notification_start(void);

void reset_device(bool reset_bad_blocks);

#ifdef CONFIG_MSENSE3_BLUETOOTH_DATA_UPDATES
void ppg_send(struct bt_conn *conn, const uint8_t *data, uint16_t len);
static ssize_t read_ppg_quality(struct bt_conn *,const struct bt_gatt_attr *, void *, uint16_t , uint16_t );
#endif
 #endif
```

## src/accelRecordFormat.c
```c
#include "accelRecordFormat.h"

#include <string.h>

#include <zephyr/sys/crc.h>

static void accel_record_format_put_u16_le(uint8_t *dst, uint16_t value)
{
	dst[0] = (uint8_t)(value & 0xffU);
	dst[1] = (uint8_t)(value >> 8);
}

static void accel_record_format_put_u32_le(uint8_t *dst, uint32_t value)
{
	dst[0] = (uint8_t)(value & 0xffU);
	dst[1] = (uint8_t)((value >> 8) & 0xffU);
	dst[2] = (uint8_t)((value >> 16) & 0xffU);
	dst[3] = (uint8_t)((value >> 24) & 0xffU);
}

void accel_record_format_build_header(uint8_t *header)
{
	uint32_t crc;

	memset(header, 0, ACCEL_RECORD_FORMAT_BLOCK_BYTES);
	header[0] = 'A';
	header[1] = 'C';
	header[2] = 'F';
	header[3] = '3';
	accel_record_format_put_u16_le(&header[4], ACCEL_RECORD_FORMAT_VERSION);
	accel_record_format_put_u16_le(&header[6],
				      ACCEL_RECORD_FORMAT_SAMPLE_FORMAT_FSYNC_X_LSB);
	accel_record_format_put_u32_le(&header[8], 1125U);
	accel_record_format_put_u32_le(&header[12], 2U);
	accel_record_format_put_u16_le(&header[16], 2U);
	accel_record_format_put_u16_le(&header[18], 16384U);
	accel_record_format_put_u32_le(&header[24],
				      ACCEL_RECORD_FORMAT_RTC_TICKS_PER_SECOND);
	accel_record_format_put_u32_le(&header[28],
				      ACCEL_RECORD_FORMAT_FSYNC_EDGE_INTERVAL_TICKS);
	header[32] = ACCEL_RECORD_FORMAT_FSYNC_AXIS_X;
	header[33] = ACCEL_RECORD_FORMAT_FSYNC_BIT;
	header[34] = ACCEL_RECORD_FORMAT_TIMESTAMP_ALGORITHM;
	header[35] = ACCEL_RECORD_FORMAT_TIMESTAMP_WINDOW;

	crc = crc32_ieee(header, ACCEL_RECORD_FORMAT_BLOCK_BYTES);
	accel_record_format_put_u32_le(&header[20], crc);
}

void accel_record_format_build_trailer(uint8_t *trailer,
					       uint32_t valid_data_bytes)
{
	uint32_t crc;

	memset(trailer, 0, ACCEL_RECORD_FORMAT_TRAILER_BYTES);
	trailer[0] = 'A';
	trailer[1] = 'C';
	trailer[2] = 'T';
	trailer[3] = '2';
	accel_record_format_put_u32_le(&trailer[4], valid_data_bytes);
	crc = crc32_ieee(trailer, ACCEL_RECORD_FORMAT_TRAILER_BYTES);
	accel_record_format_put_u32_le(&trailer[8], crc);
}

void accel_record_format_store_fifo_sample(uint8_t *block, size_t sample_index,
					   const uint8_t *fifo_sample)
{
	size_t payload_offset = ACCEL_RECORD_FORMAT_BLOCK_HEADER_BYTES +
		(sample_index * ACCEL_RECORD_FORMAT_SAMPLE_BYTES);

	block[payload_offset] = fifo_sample[1];
	block[payload_offset + 1U] = fifo_sample[0];
	block[payload_offset + 2U] = fifo_sample[3];
	block[payload_offset + 3U] = fifo_sample[2];
	block[payload_offset + 4U] = fifo_sample[5];
	block[payload_offset + 5U] = fifo_sample[4];
}

size_t accel_record_format_finalize_block(uint8_t *block, size_t sample_count,
					  uint32_t first_sample_sequence,
					  uint32_t reserved_timer_output)
{
	size_t write_length = ACCEL_RECORD_FORMAT_BLOCK_HEADER_BYTES +
		(sample_count * ACCEL_RECORD_FORMAT_SAMPLE_BYTES);
	uint32_t crc;

	block[0] = 'A';
	block[1] = 'C';
	block[2] = 'B';
	block[3] = '1';
	accel_record_format_put_u32_le(&block[4], reserved_timer_output);
	accel_record_format_put_u32_le(&block[8], first_sample_sequence);
	memset(&block[12], 0, 4U);
	crc = crc32_ieee(block, write_length);
	accel_record_format_put_u32_le(&block[12], crc);

	return write_length;
}
```
